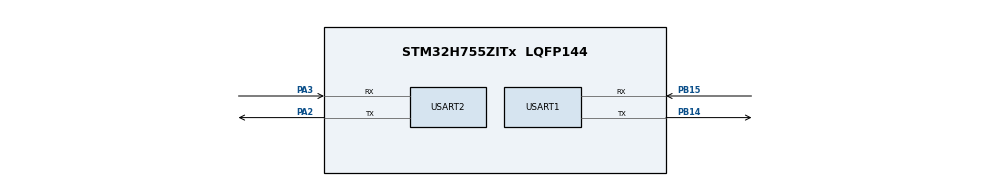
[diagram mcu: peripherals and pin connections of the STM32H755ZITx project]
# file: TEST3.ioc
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CortexM4.IPs=FATFS_M4\:I,FREERTOS_M4\:I,IWDG2\:I,RCC,WWDG2\:I,DMA,BDMA,MDMA,NVIC2\:I,ETH,USART3,DEBUG,PDM2PCM_M4\:I,PWR,RESMGR_UTILITY,SYS_M4\:I,USB_DEVICE_M4\:I,USB_HOST_M4\:I,CORTEX_M4\:I,GPIO,OPENAMP_M4\:I,VREFBUF,NUCLEO-H755ZI-Q
CortexM7.IPs=FATFS_M7\:I,FREERTOS_M7\:I,IWDG1\:I,RCC\:I,WWDG1\:I,DMA\:I,BDMA\:I,MDMA\:I,NVIC1\:I,ETH\:I,USART3\:I,USB_OTG_FS\:I,USB_OTG_FS1\:I,SYS\:I,CORTEX_M7\:I,DEBUG\:I,PDM2PCM_M7\:I,PWR\:I,RESMGR_UTILITY\:I,USB_DEVICE_M7\:I,USB_HOST_M7\:I,GPIO\:I,OPENAMP_M7\:I,VREFBUF\:I,NUCLEO-H755ZI-Q\:I,USART1\:I,USART2\:I
Dma.Request0=USART1_RX
Dma.Request1=USART1_TX
Dma.Request2=USART2_TX
Dma.USART1_RX.0.Direction=DMA_PERIPH_TO_MEMORY
Dma.USART1_RX.0.EventEnable=DISABLE
Dma.USART1_RX.0.FIFOMode=DMA_FIFOMODE_DISABLE
Dma.USART1_RX.0.Instance=DMA1_Stream0
Dma.USART1_RX.0.MemDataAlignment=DMA_MDATAALIGN_BYTE
Dma.USART1_RX.0.MemInc=DMA_MINC_ENABLE
Dma.USART1_RX.0.Mode=DMA_CIRCULAR
Dma.USART1_RX.0.PeriphDataAlignment=DMA_PDATAALIGN_BYTE
Dma.USART1_RX.0.PeriphInc=DMA_PINC_DISABLE
Dma.USART1_RX.0.Polarity=HAL_DMAMUX_REQ_GEN_RISING
Dma.USART1_RX.0.Priority=DMA_PRIORITY_LOW
Dma.USART1_RX.0.RequestNumber=1
Dma.USART1_RX.0.SignalID=NONE
Dma.USART1_RX.0.SyncEnable=DISABLE
Dma.USART1_RX.0.SyncPolarity=HAL_DMAMUX_SYNC_NO_EVENT
Dma.USART1_RX.0.SyncRequestNumber=1
Dma.USART1_RX.0.SyncSignalID=NONE
Dma.USART1_TX.1.Direction=DMA_MEMORY_TO_PERIPH
Dma.USART1_TX.1.EventEnable=DISABLE
Dma.USART1_TX.1.FIFOMode=DMA_FIFOMODE_DISABLE
Dma.USART1_TX.1.Instance=DMA1_Stream1
Dma.USART1_TX.1.MemDataAlignment=DMA_MDATAALIGN_BYTE
Dma.USART1_TX.1.MemInc=DMA_MINC_ENABLE
Dma.USART1_TX.1.Mode=DMA_NORMAL
Dma.USART1_TX.1.PeriphDataAlignment=DMA_PDATAALIGN_BYTE
Dma.USART1_TX.1.PeriphInc=DMA_PINC_DISABLE
Dma.USART1_TX.1.Polarity=HAL_DMAMUX_REQ_GEN_RISING
Dma.USART1_TX.1.Priority=DMA_PRIORITY_LOW
Dma.USART1_TX.1.RequestNumber=1
Dma.USART1_TX.1.SignalID=NONE
Dma.USART1_TX.1.SyncEnable=DISABLE
Dma.USART1_TX.1.SyncPolarity=HAL_DMAMUX_SYNC_NO_EVENT
Dma.USART1_TX.1.SyncRequestNumber=1
Dma.USART1_TX.1.SyncSignalID=NONE
Dma.USART2_TX.2.Direction=DMA_MEMORY_TO_PERIPH
Dma.USART2_TX.2.EventEnable=DISABLE
Dma.USART2_TX.2.FIFOMode=DMA_FIFOMODE_DISABLE
Dma.USART2_TX.2.Instance=DMA1_Stream2
Dma.USART2_TX.2.MemDataAlignment=DMA_MDATAALIGN_BYTE
Dma.USART2_TX.2.MemInc=DMA_MINC_ENABLE
Dma.USART2_TX.2.Mode=DMA_NORMAL
Dma.USART2_TX.2.PeriphDataAlignment=DMA_PDATAALIGN_BYTE
Dma.USART2_TX.2.PeriphInc=DMA_PINC_DISABLE
Dma.USART2_TX.2.Polarity=HAL_DMAMUX_REQ_GEN_RISING
Dma.USART2_TX.2.Priority=DMA_PRIORITY_LOW
Dma.USART2_TX.2.RequestNumber=1
Dma.USART2_TX.2.SignalID=NONE
Dma.USART2_TX.2.SyncEnable=DISABLE
Dma.USART2_TX.2.SyncPolarity=HAL_DMAMUX_SYNC_NO_EVENT
Dma.USART2_TX.2.SyncRequestNumber=1
Dma.USART2_TX.2.SyncSignalID=NONE
Mcu.Family=STM32H7
Mcu.Name=STM32H755ZITx
Mcu.Package=LQFP144
NVIC1.DMA1_Stream0_IRQn=true\:0\:0\:false\:false\:true\:false\:true\:true
NVIC1.DMA1_Stream1_IRQn=true\:0\:0\:false\:false\:true\:false\:true\:true
NVIC1.DMA1_Stream2_IRQn=true\:0\:0\:false\:false\:true\:false\:true\:true
NVIC1.PriorityGroup=NVIC_PRIORITYGROUP_4
NVIC1.USART1_IRQn=true\:0\:0\:false\:false\:true\:true\:true\:true
NVIC1.USART2_IRQn=true\:0\:0\:false\:false\:true\:true\:true\:true
NVIC2.PriorityGroup=NVIC_PRIORITYGROUP_4
PA2.Mode=Asynchronous
PA2.PinAttribute=CortexM7
PA2.Signal=USART2_TX
PA3.Mode=Asynchronous
PA3.PinAttribute=CortexM7
PA3.Signal=USART2_RX
PB0.TagName=LD1
PB14.Mode=Asynchronous
PB14.PinAttribute=CortexM7
PB14.Signal=USART1_TX
PB14.TagName=LD3
PB15.Mode=Asynchronous
PB15.PinAttribute=CortexM7
PB15.Signal=USART1_RX
PC13.TagName=BUTTON
PD8.TagName=VCP_RX
PD9.TagName=VCP_TX
PE1.TagName=LD2
ProjectManager.HeapSize=M4-0x200,M7-0x200
ProjectManager.StackSize=M4-0x400,M7-0x400
ProjectManager.TargetToolchain=STM32CubeIDE
RCC.ADCFreq_Value=129000000
RCC.APB1Freq_Value=112500000
RCC.APB2Freq_Value=112500000
RCC.APB3Freq_Value=112500000
RCC.APB4Freq_Value=112500000
RCC.CortexFreq_Value=225000000
RCC.D1PPRE=RCC_APB3_DIV2
RCC.D2PPRE1=RCC_APB1_DIV2
RCC.D2PPRE2=RCC_APB2_DIV2
RCC.D3PPRE=RCC_APB4_DIV2
RCC.DIVM1=4
RCC.DIVN1=28
RCC.DIVQ1=5
RCC.HCLKFreq_Value=225000000
RCC.PLL2FRACN=0
RCC.PLL3FRACN=0
RCC.PLLFRACN=1024
RCC.SYSCLKFreq_VALUE=225000000
RCC.SYSCLKSource=RCC_SYSCLKSOURCE_PLLCLK
RCC.SupplySource=PWR_DIRECT_SMPS_SUPPLY
RCC.USBFreq_Value=90000000
USART1.VirtualMode-Asynchronous=VM_ASYNC
USART2.VirtualMode-Asynchronous=VM_ASYNC
VP_SYS_M4_VS_Systick.Mode=SysTick
board=NUCLEO-H755ZI-Q

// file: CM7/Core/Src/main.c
/* USER CODE BEGIN Header */
/**
  ******************************************************************************
  * @file           : main.c
  * @brief          : Main program body - NUCLEO-H755ZI-Q (CM7 only)
  ******************************************************************************
  */
/* USER CODE END Header */
#include "main.h"
#include "string.h"

/* USER CODE BEGIN PD */

// Dual core sync is DISABLED
// #define DUAL_CORE_BOOT_SYNC_SEQUENCE

#if defined(DUAL_CORE_BOOT_SYNC_SEQUENCE)
#ifndef HSEM_ID_0
#define HSEM_ID_0 (0U)
#endif
#endif

/* USER CODE END PD */

UART_HandleTypeDef huart1;
UART_HandleTypeDef huart2;
DMA_HandleTypeDef hdma_usart1_rx;
DMA_HandleTypeDef hdma_usart1_tx;
DMA_HandleTypeDef hdma_usart2_tx;

void SystemClock_Config(void);
static void MX_GPIO_Init(void);
static void MX_DMA_Init(void);
static void MX_USART1_UART_Init(void);
static void MX_USART2_UART_Init(void);

int main(void)
{

  /* MCU Configuration--------------------------------------------------------*/
  HAL_Init();

  /* Configure the system clock */
  SystemClock_Config();

  /* Initialize all configured peripherals */
  MX_GPIO_Init();
  MX_DMA_Init();
  MX_USART1_UART_Init();
  MX_USART2_UART_Init();

  /* USER CODE BEGIN 2 */

  // Optional: Start USART1 DMA reception later when you add protocol
  // HAL_UARTEx_ReceiveToIdle_DMA(&huart1, g_dma_buffer, DMA_BUFFER_SIZE);

  /* USER CODE END 2 */

  /* Infinite loop */
  while (1)
  {

    /* ========== STATUS LED + DOCKLIGHT TEST ========== */
    HAL_GPIO_TogglePin(GPIOB, GPIO_PIN_0);          // Green LED toggle

    HAL_UART_Transmit(&huart2, (uint8_t*)"H755 Running\r\n", 14, 100);

    HAL_Delay(500);
    /* ================================================= */

  }
}

void SystemClock_Config(void)
{
  RCC_OscInitTypeDef RCC_OscInitStruct = {0};
  RCC_ClkInitTypeDef RCC_ClkInitStruct = {0};

  /** Supply configuration update enable */
  HAL_PWREx_ConfigSupply(PWR_DIRECT_SMPS_SUPPLY);

  /** Configure the main internal regulator output voltage */
  __HAL_PWR_VOLTAGESCALING_CONFIG(PWR_REGULATOR_VOLTAGE_SCALE3);

  while(!__HAL_PWR_GET_FLAG(PWR_FLAG_VOSRDY)) {}

  /** Initializes the RCC Oscillators */
  RCC_OscInitStruct.OscillatorType = RCC_OSCILLATORTYPE_HSI;
  RCC_OscInitStruct.HSIState = RCC_HSI_DIV1;
  RCC_OscInitStruct.HSICalibrationValue = RCC_HSICALIBRATION_DEFAULT;
  RCC_OscInitStruct.PLL.PLLState = RCC_PLL_NONE;

  if (HAL_RCC_OscConfig(&RCC_OscInitStruct) != HAL_OK)
  {
    Error_Handler();
  }

  /** Initializes the CPU, AHB and APB buses clocks */
  RCC_ClkInitStruct.ClockType = RCC_CLOCKTYPE_HCLK|RCC_CLOCKTYPE_SYSCLK
                              |RCC_CLOCKTYPE_PCLK1|RCC_CLOCKTYPE_PCLK2
                              |RCC_CLOCKTYPE_D3PCLK1|RCC_CLOCKTYPE_D1PCLK1;
  RCC_ClkInitStruct.SYSCLKSource = RCC_SYSCLKSOURCE_HSI;
  RCC_ClkInitStruct.SYSCLKDivider = RCC_SYSCLK_DIV1;
  RCC_ClkInitStruct.AHBCLKDivider = RCC_HCLK_DIV1;
  RCC_ClkInitStruct.APB3CLKDivider = RCC_APB3_DIV1;
  RCC_ClkInitStruct.APB1CLKDivider = RCC_APB1_DIV1;
  RCC_ClkInitStruct.APB2CLKDivider = RCC_APB2_DIV1;
  RCC_ClkInitStruct.APB4CLKDivider = RCC_APB4_DIV1;

  if (HAL_RCC_ClockConfig(&RCC_ClkInitStruct, FLASH_LATENCY_1) != HAL_OK)
  {
    Error_Handler();
  }
}

static void MX_USART1_UART_Init(void)
{
  huart1.Instance = USART1;
  huart1.Init.BaudRate = 115200;
  huart1.Init.WordLength = UART_WORDLENGTH_8B;
  huart1.Init.StopBits = UART_STOPBITS_1;
  huart1.Init.Parity = UART_PARITY_NONE;
  huart1.Init.Mode = UART_MODE_TX_RX;
  huart1.Init.HwFlowCtl = UART_HWCONTROL_NONE;
  huart1.Init.OverSampling = UART_OVERSAMPLING_16;
  huart1.Init.OneBitSampling = UART_ONE_BIT_SAMPLE_DISABLE;
  huart1.Init.ClockPrescaler = UART_PRESCALER_DIV1;
  huart1.AdvancedInit.AdvFeatureInit = UART_ADVFEATURE_NO_INIT;

  if (HAL_UART_Init(&huart1) != HAL_OK)
  {
    Error_Handler();
  }
  if (HAL_UARTEx_SetTxFifoThreshold(&huart1, UART_TXFIFO_THRESHOLD_1_8) != HAL_OK)
  {
    Error_Handler();
  }
  if (HAL_UARTEx_SetRxFifoThreshold(&huart1, UART_RXFIFO_THRESHOLD_1_8) != HAL_OK)
  {
    Error_Handler();
  }
  if (HAL_UARTEx_DisableFifoMode(&huart1) != HAL_OK)
  {
    Error_Handler();
  }
}

static void MX_USART2_UART_Init(void)
{
  huart2.Instance = USART2;
  huart2.Init.BaudRate = 115200;
  huart2.Init.WordLength = UART_WORDLENGTH_8B;
  huart2.Init.StopBits = UART_STOPBITS_1;
  huart2.Init.Parity = UART_PARITY_NONE;
  huart2.Init.Mode = UART_MODE_TX_RX;
  huart2.Init.HwFlowCtl = UART_HWCONTROL_NONE;
  huart2.Init.OverSampling = UART_OVERSAMPLING_16;
  huart2.Init.OneBitSampling = UART_ONE_BIT_SAMPLE_DISABLE;
  huart2.Init.ClockPrescaler = UART_PRESCALER_DIV1;
  huart2.AdvancedInit.AdvFeatureInit = UART_ADVFEATURE_NO_INIT;

  if (HAL_UART_Init(&huart2) != HAL_OK)
  {
    Error_Handler();
  }
  if (HAL_UARTEx_SetTxFifoThreshold(&huart2, UART_TXFIFO_THRESHOLD_1_8) != HAL_OK)
  {
    Error_Handler();
  }
  if (HAL_UARTEx_SetRxFifoThreshold(&huart2, UART_RXFIFO_THRESHOLD_1_8) != HAL_OK)
  {
    Error_Handler();
  }
  if (HAL_UARTEx_DisableFifoMode(&huart2) != HAL_OK)
  {
    Error_Handler();
  }
}

static void MX_DMA_Init(void)
{
  __HAL_RCC_DMA1_CLK_ENABLE();

  HAL_NVIC_SetPriority(DMA1_Stream0_IRQn, 0, 0);
  HAL_NVIC_EnableIRQ(DMA1_Stream0_IRQn);
  HAL_NVIC_SetPriority(DMA1_Stream1_IRQn, 0, 0);
  HAL_NVIC_EnableIRQ(DMA1_Stream1_IRQn);
  HAL_NVIC_SetPriority(DMA1_Stream2_IRQn, 0, 0);
  HAL_NVIC_EnableIRQ(DMA1_Stream2_IRQn);
}

static void MX_GPIO_Init(void)
{
  GPIO_InitTypeDef GPIO_InitStruct = {0};

  __HAL_RCC_GPIOA_CLK_ENABLE();
  __HAL_RCC_GPIOB_CLK_ENABLE();

  /* Configure PB0 as Output (Green Status LED) */
  HAL_GPIO_WritePin(GPIOB, GPIO_PIN_0, GPIO_PIN_RESET);

  GPIO_InitStruct.Pin = GPIO_PIN_0;
  GPIO_InitStruct.Mode = GPIO_MODE_OUTPUT_PP;
  GPIO_InitStruct.Pull = GPIO_NOPULL;
  GPIO_InitStruct.Speed = GPIO_SPEED_FREQ_LOW;
  HAL_GPIO_Init(GPIOB, &GPIO_InitStruct);
}

void Error_Handler(void)
{
  __disable_irq();
  while (1)
  {
  }
}
